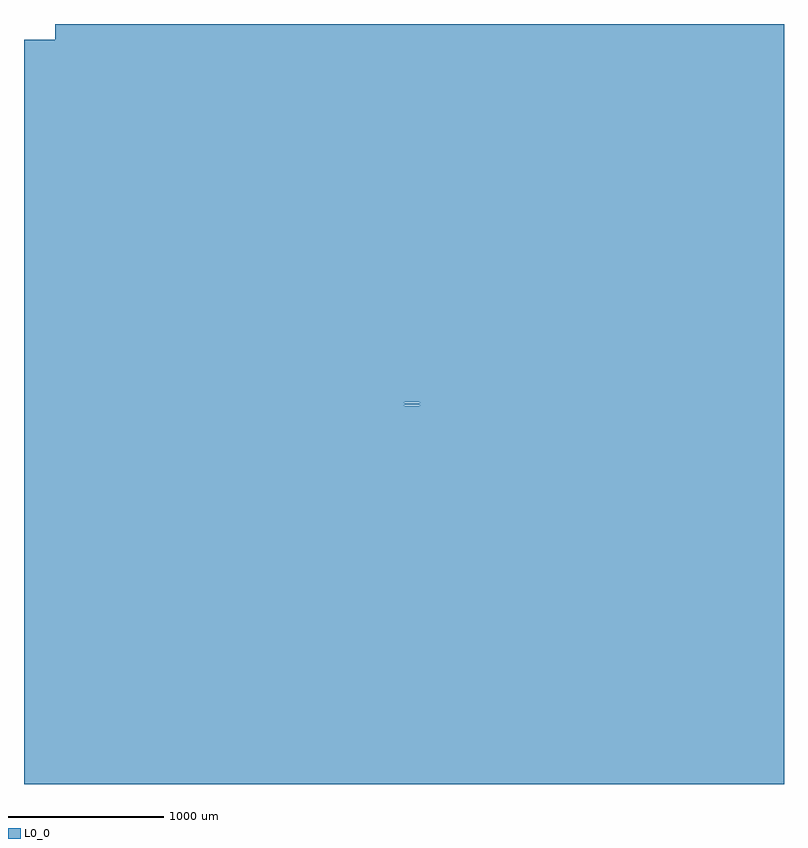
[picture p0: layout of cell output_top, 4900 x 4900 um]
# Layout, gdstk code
import gdstk
lib = gdstk.Library(unit=1e-6, precision=1e-09)
def R(c, l, rs):  # rectangles x0, y0, x1, y1
    for r in rs: c.add(gdstk.rectangle(r[:2], r[2:], *l))
def A(c, l, x, y, w, h, nx, ny, dx, dy):  # array of equal rectangles
    R(c, l, [(x+i*dx, y+j*dy, x+i*dx+w, y+j*dy+h) for i in range(nx) for j in range(ny)])
def P(c, l, *ps):  # polygons
    for p in ps: c.add(gdstk.Polygon(p, *l))
L0_0 = (0, 0)

output_top = lib.new_cell('output_top')
A(output_top, L0_0, -1960, -2450, 490, 4900, 4, 1, 490, 0)
A(output_top, L0_0, 490, -2450, 490, 4900, 4, 1, 490, 0)
A(output_top, L0_0, 0, -21, 100, 10, 1, 3, 0, 16)
P(output_top, L0_0, [(-1960,2450),(-2250,2450),(-2250,2350),(-2450,2350),(-2450,-2450),(-1960,-2450)],
  [(490,2450),(0,2450),(0,21),(100,21),(100,-21),(0,-21),(0,-2450),(490,-2450)])

lib.write_gds('output_top.gds')
